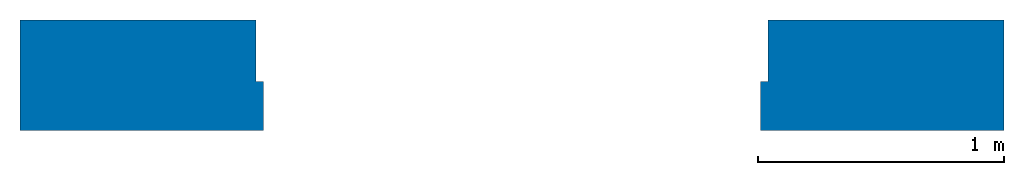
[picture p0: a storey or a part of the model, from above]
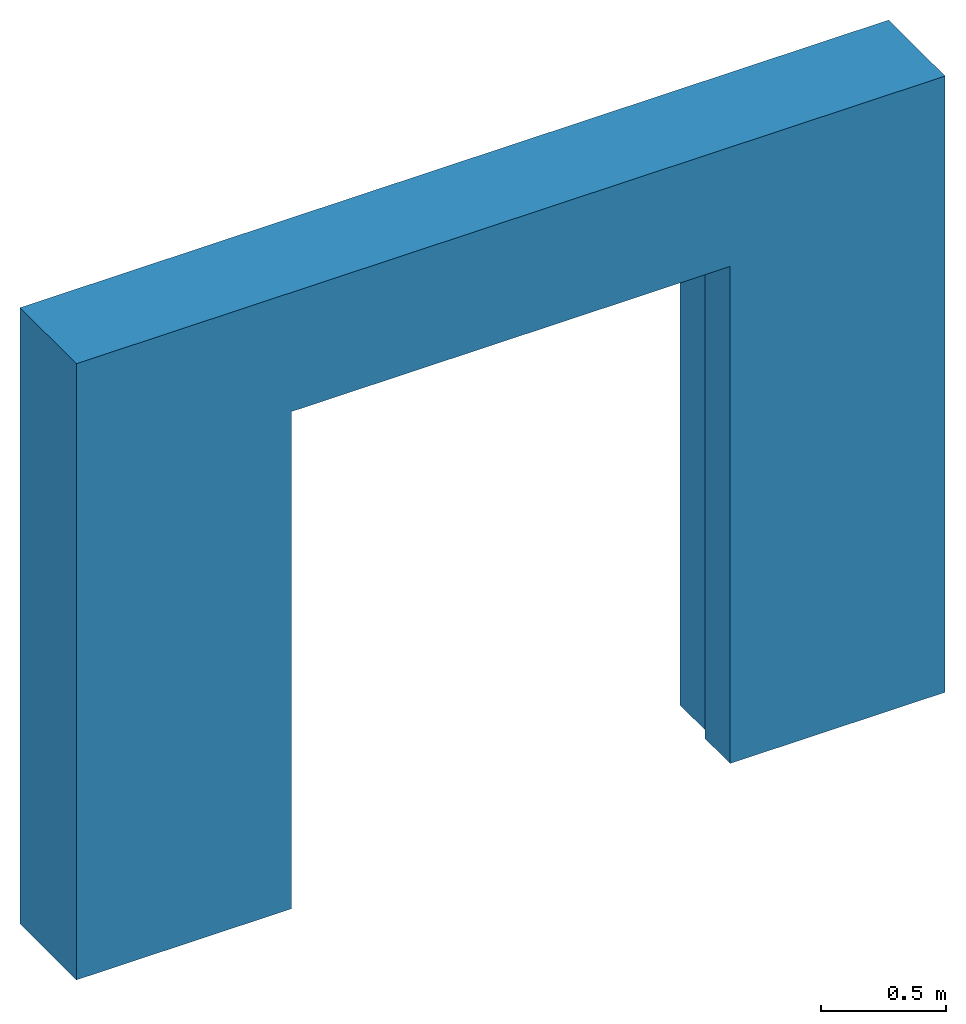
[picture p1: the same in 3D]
Properties of the parts of a building model (IFC4)

# File
Description: no view
File name: ÖBV_OEBV_Richtlinie_Balkon_Loggia.ifc
Time: 2024-03-13T09:41:38
Author: Oesterreichische Bautechnik Vereinigung
Organization: OEBV
Written by: ODA SDAI 24.5
Authorization: OEBV

# IfcSite, Liegenschaft
RefLatitude: 48, 8, 10, 320000; RefLongitude: 11, 41, 19, 320000

# IfcBuildingStorey (2)
In: Gebäude
Elevation: 0 m
Name
Geschoss 01
Geschoss 02

# IfcBeam
In: Geschoss 01
Material: Mineralwolledämmung
AllplanAttributes - Allright_Bauteil_ID: 0013Unz0000168689

# IfcBuildingElementProxy (6)
In: Geschoss 01
Name | Allright_Bauteil_ID
macro | 0013Mak0000163416
macro | 0013Mak0000163445
macro | 0013Mak0000163459
macro | 0013Mak0000163468
macro | 0013Mak0000163477
macro | 0013Mak0000163488

# IfcElementAssembly (6)
In: Geschoss 01
Name | Allright_Bauteil_ID
SpatialDim_Group | 0013Elg0000163417
SpatialDim_Group | 0013Elg0000163446
SpatialDim_Group | 0013Elg0000163460
SpatialDim_Group | 0013Elg0000163469
SpatialDim_Group | 0013Elg0000163478
SpatialDim_Group | 0013Elg0000163489

# IfcOpeningElement: Opening, Türöffnung
In: Geschoss 02
AllplanAttributes - Object Layer Attributes #1, Allright_Bauteil_ID: 0063Tür0000000007; Object Layer Attributes #2, Allright_Bauteil_ID: 0063Tür0000000009

# IfcSlab (2)
In: Geschoss 01
PredefinedType: FLOOR
Name | Allright_Bauteil_ID
 | 0013De 0000167371
 | 0013De 0000167377

# IfcWall (3)
Name | In | Material | Allright_Bauteil_ID | Object Layer Attributes #1, Allright_Bauteil_ID
 | Geschoss 01 | layer 0.2 m | 0013HWa0000167404 | 0013Wa 0000167405
 | Geschoss 01 | layer 0.2 m | 0013HWa0000167410 | 0013Wa 0000167411
WA_01 | Geschoss 02 | C20/25 0.25 m, layer 0.2 m | 0063HWa0000000003 | 0063Wa 0000000014 | AllplanAttributes - Object Layer Attributes #2, Allright_Bauteil_ID: 0063Wa 0000000018
